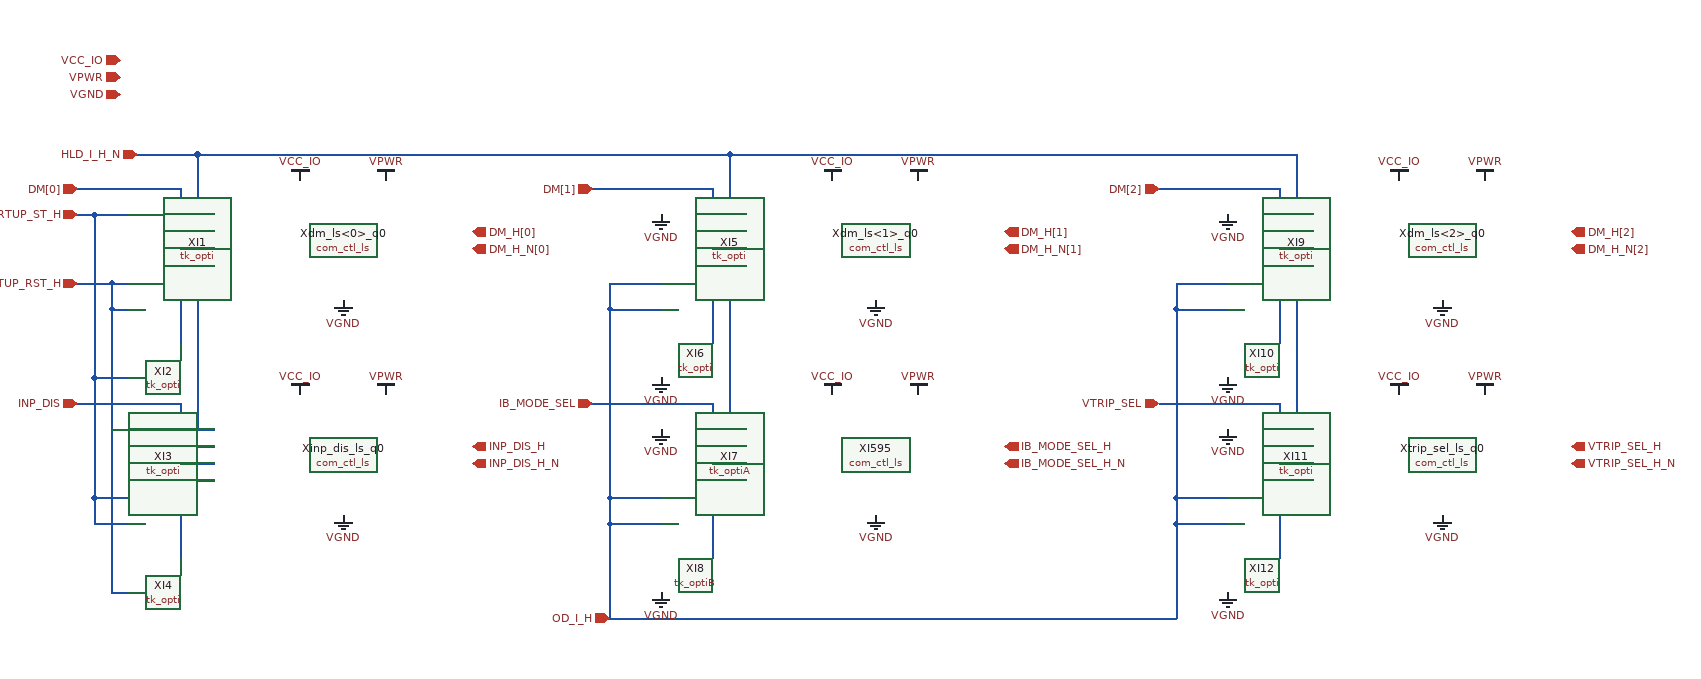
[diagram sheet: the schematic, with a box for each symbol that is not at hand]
v {xschem version=2.9.9 file_version=1.2 
* Copyright 2023 David Mitchell Bailey
* 
* Licensed under the Apache License, Version 2.0 (the "License");
* you may not use this file except in compliance with the License.
* You may obtain a copy of the License at
* 
*     https://www.apache.org/licenses/LICENSE-2.0
* 
* Unless required by applicable law or agreed to in writing, software
* distributed under the License is distributed on an "AS IS" BASIS,
* WITHOUT WARRANTIES OR CONDITIONS OF ANY KIND, either express or implied.
* See the License for the specific language governing permissions and
* limitations under the License.
}
G {}
K {}
V {}
S {}
E {}
N 10 -680 80 -680 { lab=HLD_I_H_N}
N 80 -680 80 -610 { lab=HLD_I_H_N}
N 80 -610 100 -610 { lab=HLD_I_H_N}
N -60 -640 60 -640 { lab=DM[0]}
N 60 -640 60 -590 { lab=DM[0]}
N 60 -590 100 -590 { lab=DM[0]}
N 60 -570 100 -570 { lab=#net1}
N 60 -550 60 -460 { lab=#net2}
N 60 -550 100 -550 { lab=#net2}
N 80 -360 100 -360 { lab=HLD_I_H_N}
N -60 -390 60 -390 { lab=INP_DIS}
N 60 -390 60 -340 { lab=INP_DIS}
N 60 -340 100 -340 { lab=INP_DIS}
N 60 -320 100 -320 { lab=#net3}
N 60 -300 60 -210 { lab=#net4}
N 60 -300 100 -300 { lab=#net4}
N 700 -680 700 -610 { lab=HLD_I_H_N}
N 700 -610 720 -610 { lab=HLD_I_H_N}
N 540 -640 680 -640 { lab=DM[1]}
N 680 -640 680 -590 { lab=DM[1]}
N 680 -590 720 -590 { lab=DM[1]}
N 680 -570 720 -570 { lab=#net5}
N 680 -550 680 -460 { lab=#net6}
N 680 -550 720 -550 { lab=#net6}
N 700 -360 720 -360 { lab=HLD_I_H_N}
N 540 -390 680 -390 { lab=IB_MODE_SEL}
N 680 -390 680 -340 { lab=IB_MODE_SEL}
N 680 -340 720 -340 { lab=IB_MODE_SEL}
N 680 -320 720 -320 { lab=#net7}
N 680 -300 680 -210 { lab=#net8}
N 680 -300 720 -300 { lab=#net8}
N 700 -680 1360 -680 { lab=HLD_I_H_N}
N 1360 -680 1360 -610 { lab=HLD_I_H_N}
N 1360 -610 1380 -610 { lab=HLD_I_H_N}
N 1200 -640 1340 -640 { lab=DM[2]}
N 1340 -640 1340 -590 { lab=DM[2]}
N 1340 -590 1380 -590 { lab=DM[2]}
N 1340 -570 1380 -570 { lab=#net9}
N 1340 -550 1340 -460 { lab=#net10}
N 1340 -550 1380 -550 { lab=#net10}
N 1360 -360 1380 -360 { lab=HLD_I_H_N}
N 1200 -390 1340 -390 { lab=VTRIP_SEL}
N 1340 -390 1340 -340 { lab=VTRIP_SEL}
N 1340 -340 1380 -340 { lab=VTRIP_SEL}
N 1340 -320 1380 -320 { lab=#net11}
N 1340 -300 1340 -210 { lab=#net12}
N 1340 -300 1380 -300 { lab=#net12}
N 1220 -530 1280 -530 { lab=OD_I_H}
N 80 -610 80 -360 { lab=HLD_I_H_N}
N 1220 -250 1220 -140 { lab=OD_I_H}
N 700 -610 700 -360 { lab=HLD_I_H_N}
N 1360 -610 1360 -360 { lab=HLD_I_H_N}
N -40 -610 -0 -610 { lab=STARTUP_ST_H}
N -20 -530 -0 -530 { lab=STARTUP_RST_H}
N -20 -500 0 -500 { lab=STARTUP_RST_H}
N -40 -420 0 -420 { lab=STARTUP_ST_H}
N -20 -170 0 -170 { lab=STARTUP_ST_H}
N 1220 -500 1280 -500 { lab=OD_I_H}
N 1220 -280 1280 -280 { lab=OD_I_H}
N 1220 -250 1280 -250 { lab=OD_I_H}
N 560 -530 620 -530 { lab=OD_I_H}
N 560 -250 560 -140 { lab=OD_I_H}
N 560 -500 620 -500 { lab=OD_I_H}
N 560 -280 620 -280 { lab=OD_I_H}
N 560 -250 620 -250 { lab=OD_I_H}
N 560 -140 1220 -140 { lab=OD_I_H}
N -60 -530 -20 -530 { lab=STARTUP_RST_H}
N -60 -610 -40 -610 { lab=STARTUP_ST_H}
N -20 -530 -20 -500 { lab=STARTUP_RST_H}
N -40 -610 -40 -420 { lab=STARTUP_ST_H}
N -40 -420 -40 -280 {}
N -40 -280 0 -280 {}
N -40 -280 -40 -250 {}
N -40 -250 0 -250 {}
N 80 -680 700 -680 { lab=HLD_I_H_N}
N 1220 -530 1220 -500 { lab=OD_I_H}
N 1220 -500 1220 -280 { lab=OD_I_H}
N 1220 -280 1220 -250 { lab=OD_I_H}
N 560 -530 560 -500 { lab=OD_I_H}
N 560 -500 560 -280 { lab=OD_I_H}
N 560 -280 560 -250 { lab=OD_I_H}
N -20 -500 -20 -170 {}
N -20 -360 0 -360 {}
C {common/tk_opti.sym} 30 -570 0 0 {name=XI1 }
C {com_ctl_ls.sym} 250 -580 0 0 {name=Xdm_ls<0>_q0 }
C {common/tk_opti.sym} 30 -460 0 0 {name=XI2 }
C {devices/ipin.sym} -60 -610 0 0 {name=p1 lab=STARTUP_ST_H}
C {devices/ipin.sym} -60 -530 0 0 {name=p2 lab=STARTUP_RST_H}
C {devices/ipin.sym} -60 -640 0 0 {name=p3 lab=DM[0]}
C {devices/ipin.sym} 10 -680 0 0 {name=p4 lab=HLD_I_H_N}
C {devices/iopin.sym} -10 -790 0 0 {name=p5 lab=VCC_IO}
C {devices/iopin.sym} -10 -770 0 0 {name=p6 lab=VPWR}
C {devices/iopin.sym} -10 -750 0 0 {name=p7 lab=VGND}
C {devices/opin.sym} 400 -590 0 0 {name=p8 lab=DM_H[0]}
C {devices/opin.sym} 400 -570 0 0 {name=p9 lab=DM_H_N[0]}
C {common/gnd.sym} 250 -510 0 0 {name=l1 lab=VGND}
C {common/vdd.sym} 200 -650 0 0 {name=l2 lab=VCC_IO}
C {common/vdd.sym} 300 -650 0 0 {name=l3 lab=VPWR}
C {common/tk_opti.sym} 30 -320 0 0 {name=XI3 }
C {com_ctl_ls.sym} 250 -330 0 0 {name=Xinp_dis_ls_q0 }
C {common/tk_opti.sym} 30 -210 0 0 {name=XI4 }
C {devices/ipin.sym} -60 -390 0 0 {name=p10 lab=INP_DIS}
C {devices/opin.sym} 400 -340 0 0 {name=p12 lab=INP_DIS_H}
C {devices/opin.sym} 400 -320 0 0 {name=p13 lab=INP_DIS_H_N}
C {common/gnd.sym} 250 -260 0 0 {name=l4 lab=VGND}
C {common/vdd.sym} 200 -400 0 0 {name=l5 lab=VCC_IO}
C {common/vdd.sym} 300 -400 0 0 {name=l6 lab=VPWR}
C {common/tk_opti.sym} 650 -570 0 0 {name=XI5 }
C {com_ctl_ls.sym} 870 -580 0 0 {name=Xdm_ls<1>_q0 }
C {common/tk_opti.sym} 650 -460 0 0 {name=XI6 }
C {devices/ipin.sym} 560 -140 0 0 {name=p14 lab=OD_I_H}
C {devices/ipin.sym} 540 -640 0 0 {name=p15 lab=DM[1]}
C {devices/opin.sym} 1020 -590 0 0 {name=p17 lab=DM_H[1]}
C {devices/opin.sym} 1020 -570 0 0 {name=p18 lab=DM_H_N[1]}
C {common/gnd.sym} 870 -510 0 0 {name=l7 lab=VGND}
C {common/vdd.sym} 820 -650 0 0 {name=l8 lab=VCC_IO}
C {common/vdd.sym} 920 -650 0 0 {name=l9 lab=VPWR}
C {common/tk_optiA.sym} 650 -320 0 0 {name=XI7 }
C {com_ctl_ls.sym} 870 -330 0 0 {name=XI595 }
C {common/tk_optiB.sym} 650 -210 0 0 {name=XI8 }
C {devices/ipin.sym} 540 -390 0 0 {name=p19 lab=IB_MODE_SEL}
C {devices/opin.sym} 1020 -340 0 0 {name=p20 lab=IB_MODE_SEL_H}
C {devices/opin.sym} 1020 -320 0 0 {name=p21 lab=IB_MODE_SEL_H_N}
C {common/gnd.sym} 870 -260 0 0 {name=l10 lab=VGND}
C {common/vdd.sym} 820 -400 0 0 {name=l11 lab=VCC_IO}
C {common/vdd.sym} 920 -400 0 0 {name=l12 lab=VPWR}
C {common/gnd.sym} 620 -610 0 1 {name=l13 lab=VGND}
C {common/gnd.sym} 620 -420 0 1 {name=l14 lab=VGND}
C {common/gnd.sym} 620 -360 0 1 {name=l15 lab=VGND}
C {common/gnd.sym} 620 -170 0 1 {name=l16 lab=VGND}
C {common/tk_opti.sym} 1310 -570 0 0 {name=XI9 }
C {com_ctl_ls.sym} 1530 -580 0 0 {name=Xdm_ls<2>_q0 }
C {common/tk_opti.sym} 1310 -460 0 0 {name=XI10 }
C {devices/ipin.sym} 1200 -640 0 0 {name=p22 lab=DM[2]}
C {devices/opin.sym} 1680 -590 0 0 {name=p24 lab=DM_H[2]}
C {devices/opin.sym} 1680 -570 0 0 {name=p25 lab=DM_H_N[2]}
C {common/gnd.sym} 1530 -510 0 0 {name=l17 lab=VGND}
C {common/vdd.sym} 1480 -650 0 0 {name=l18 lab=VCC_IO}
C {common/vdd.sym} 1580 -650 0 0 {name=l19 lab=VPWR}
C {common/tk_opti.sym} 1310 -320 0 0 {name=XI11 }
C {com_ctl_ls.sym} 1530 -330 0 0 {name=Xtrip_sel_ls_q0 }
C {common/tk_opti.sym} 1310 -210 0 0 {name=XI12 }
C {devices/ipin.sym} 1200 -390 0 0 {name=p26 lab=VTRIP_SEL}
C {devices/opin.sym} 1680 -340 0 0 {name=p27 lab=VTRIP_SEL_H}
C {devices/opin.sym} 1680 -320 0 0 {name=p28 lab=VTRIP_SEL_H_N}
C {common/gnd.sym} 1530 -260 0 0 {name=l20 lab=VGND}
C {common/vdd.sym} 1480 -400 0 0 {name=l21 lab=VCC_IO}
C {common/vdd.sym} 1580 -400 0 0 {name=l22 lab=VPWR}
C {common/gnd.sym} 1280 -610 0 1 {name=l23 lab=VGND}
C {common/gnd.sym} 1280 -420 0 1 {name=l24 lab=VGND}
C {common/gnd.sym} 1280 -360 0 1 {name=l25 lab=VGND}
C {common/gnd.sym} 1280 -170 0 1 {name=l26 lab=VGND}
